VERSION 5.7 ;
  NOWIREEXTENSIONATPIN ON ;
  DIVIDERCHAR "/" ;
  BUSBITCHARS "[]" ;
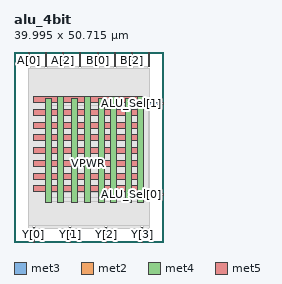
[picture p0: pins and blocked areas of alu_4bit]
MACRO alu_4bit
  CLASS BLOCK ;
  FOREIGN alu_4bit ;
  ORIGIN 0.000 0.000 ;
  SIZE 39.995 BY 50.715 ;
  PIN ALU_Sel[0]
    DIRECTION INPUT ;
    USE SIGNAL ;
    ANTENNAGATEAREA 0.213000 ;
    PORT
      LAYER met3 ;
        RECT 35.995 12.280 39.995 12.880 ;
    END
  END ALU_Sel[0]
  PIN ALU_Sel[1]
    DIRECTION INPUT ;
    USE SIGNAL ;
    ANTENNAGATEAREA 0.213000 ;
    PORT
      LAYER met3 ;
        RECT 35.995 36.760 39.995 37.360 ;
    END
  END ALU_Sel[1]
  PIN A[0]
    DIRECTION INPUT ;
    USE SIGNAL ;
    ANTENNAGATEAREA 0.196500 ;
    PORT
      LAYER met2 ;
        RECT 3.770 46.715 4.050 50.715 ;
    END
  END A[0]
  PIN A[1]
    DIRECTION INPUT ;
    USE SIGNAL ;
    ANTENNAGATEAREA 0.196500 ;
    PORT
      LAYER met2 ;
        RECT 8.370 46.715 8.650 50.715 ;
    END
  END A[1]
  PIN A[2]
    DIRECTION INPUT ;
    USE SIGNAL ;
    ANTENNAGATEAREA 0.196500 ;
    PORT
      LAYER met2 ;
        RECT 12.970 46.715 13.250 50.715 ;
    END
  END A[2]
  PIN A[3]
    DIRECTION INPUT ;
    USE SIGNAL ;
    ANTENNAGATEAREA 0.196500 ;
    PORT
      LAYER met2 ;
        RECT 17.570 46.715 17.850 50.715 ;
    END
  END A[3]
  PIN B[0]
    DIRECTION INPUT ;
    USE SIGNAL ;
    ANTENNAGATEAREA 0.213000 ;
    PORT
      LAYER met2 ;
        RECT 22.170 46.715 22.450 50.715 ;
    END
  END B[0]
  PIN B[1]
    DIRECTION INPUT ;
    USE SIGNAL ;
    ANTENNAGATEAREA 0.196500 ;
    PORT
      LAYER met2 ;
        RECT 26.770 46.715 27.050 50.715 ;
    END
  END B[1]
  PIN B[2]
    DIRECTION INPUT ;
    USE SIGNAL ;
    ANTENNAGATEAREA 0.196500 ;
    PORT
      LAYER met2 ;
        RECT 31.370 46.715 31.650 50.715 ;
    END
  END B[2]
  PIN B[3]
    DIRECTION INPUT ;
    USE SIGNAL ;
    ANTENNAGATEAREA 0.196500 ;
    PORT
      LAYER met2 ;
        RECT 35.970 46.715 36.250 50.715 ;
    END
  END B[3]
  PIN VGND
    DIRECTION INOUT ;
    USE GROUND ;
    PORT
      LAYER met4 ;
        RECT 11.585 10.640 13.185 38.760 ;
    END
    PORT
      LAYER met4 ;
        RECT 18.715 10.640 20.315 38.760 ;
    END
    PORT
      LAYER met4 ;
        RECT 25.845 10.640 27.445 38.760 ;
    END
    PORT
      LAYER met4 ;
        RECT 32.975 10.640 34.575 38.760 ;
    END
    PORT
      LAYER met5 ;
        RECT 5.280 16.775 34.575 18.375 ;
    END
    PORT
      LAYER met5 ;
        RECT 5.280 23.570 34.575 25.170 ;
    END
    PORT
      LAYER met5 ;
        RECT 5.280 30.365 34.575 31.965 ;
    END
    PORT
      LAYER met5 ;
        RECT 5.280 37.160 34.575 38.760 ;
    END
  END VGND
  PIN VPWR
    DIRECTION INOUT ;
    USE POWER ;
    PORT
      LAYER met4 ;
        RECT 8.285 10.640 9.885 38.320 ;
    END
    PORT
      LAYER met4 ;
        RECT 15.415 10.640 17.015 38.320 ;
    END
    PORT
      LAYER met4 ;
        RECT 22.545 10.640 24.145 38.320 ;
    END
    PORT
      LAYER met4 ;
        RECT 29.675 10.640 31.275 38.320 ;
    END
    PORT
      LAYER met5 ;
        RECT 5.280 13.475 34.280 15.075 ;
    END
    PORT
      LAYER met5 ;
        RECT 5.280 20.270 34.280 21.870 ;
    END
    PORT
      LAYER met5 ;
        RECT 5.280 27.065 34.280 28.665 ;
    END
    PORT
      LAYER met5 ;
        RECT 5.280 33.860 34.280 35.460 ;
    END
  END VPWR
  PIN Y[0]
    DIRECTION OUTPUT TRISTATE ;
    USE SIGNAL ;
    ANTENNADIFFAREA 0.795200 ;
    PORT
      LAYER met2 ;
        RECT 5.150 0.000 5.430 4.000 ;
    END
  END Y[0]
  PIN Y[1]
    DIRECTION OUTPUT TRISTATE ;
    USE SIGNAL ;
    ANTENNADIFFAREA 0.795200 ;
    PORT
      LAYER met2 ;
        RECT 14.810 0.000 15.090 4.000 ;
    END
  END Y[1]
  PIN Y[2]
    DIRECTION OUTPUT TRISTATE ;
    USE SIGNAL ;
    ANTENNADIFFAREA 0.795200 ;
    PORT
      LAYER met2 ;
        RECT 24.470 0.000 24.750 4.000 ;
    END
  END Y[2]
  PIN Y[3]
    DIRECTION OUTPUT TRISTATE ;
    USE SIGNAL ;
    ANTENNADIFFAREA 0.795200 ;
    PORT
      LAYER met2 ;
        RECT 34.130 0.000 34.410 4.000 ;
    END
  END Y[3]
  OBS
      LAYER li1 ;
        RECT 5.520 10.795 34.040 38.165 ;
      LAYER met1 ;
        RECT 3.750 10.640 36.270 38.320 ;
      LAYER met2 ;
        RECT 4.330 46.435 8.090 46.715 ;
        RECT 8.930 46.435 12.690 46.715 ;
        RECT 13.530 46.435 17.290 46.715 ;
        RECT 18.130 46.435 21.890 46.715 ;
        RECT 22.730 46.435 26.490 46.715 ;
        RECT 27.330 46.435 31.090 46.715 ;
        RECT 31.930 46.435 35.690 46.715 ;
        RECT 3.780 4.280 36.240 46.435 ;
        RECT 3.780 3.670 4.870 4.280 ;
        RECT 5.710 3.670 14.530 4.280 ;
        RECT 15.370 3.670 24.190 4.280 ;
        RECT 25.030 3.670 33.850 4.280 ;
        RECT 34.690 3.670 36.240 4.280 ;
      LAYER met3 ;
        RECT 8.295 37.760 35.995 38.245 ;
        RECT 8.295 36.360 35.595 37.760 ;
        RECT 8.295 13.280 35.995 36.360 ;
        RECT 8.295 11.880 35.595 13.280 ;
        RECT 8.295 10.715 35.995 11.880 ;
  END
END alu_4bit
END LIBRARY

